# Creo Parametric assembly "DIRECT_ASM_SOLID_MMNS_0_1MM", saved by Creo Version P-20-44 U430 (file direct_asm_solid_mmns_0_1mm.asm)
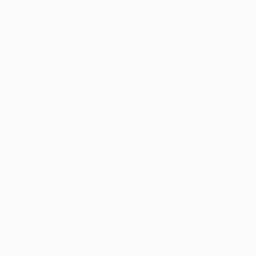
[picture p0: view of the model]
Units: millimeter Newton Second (mmNs); MM, TONNE, SECS

Created from: MMNS_ASM_DESIGN.ASM

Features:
  1. datum plane "ASM_RIGHT"
  2. datum plane "ASM_TOP"
  3. datum plane "ASM_FRONT"
  4. coordinate system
